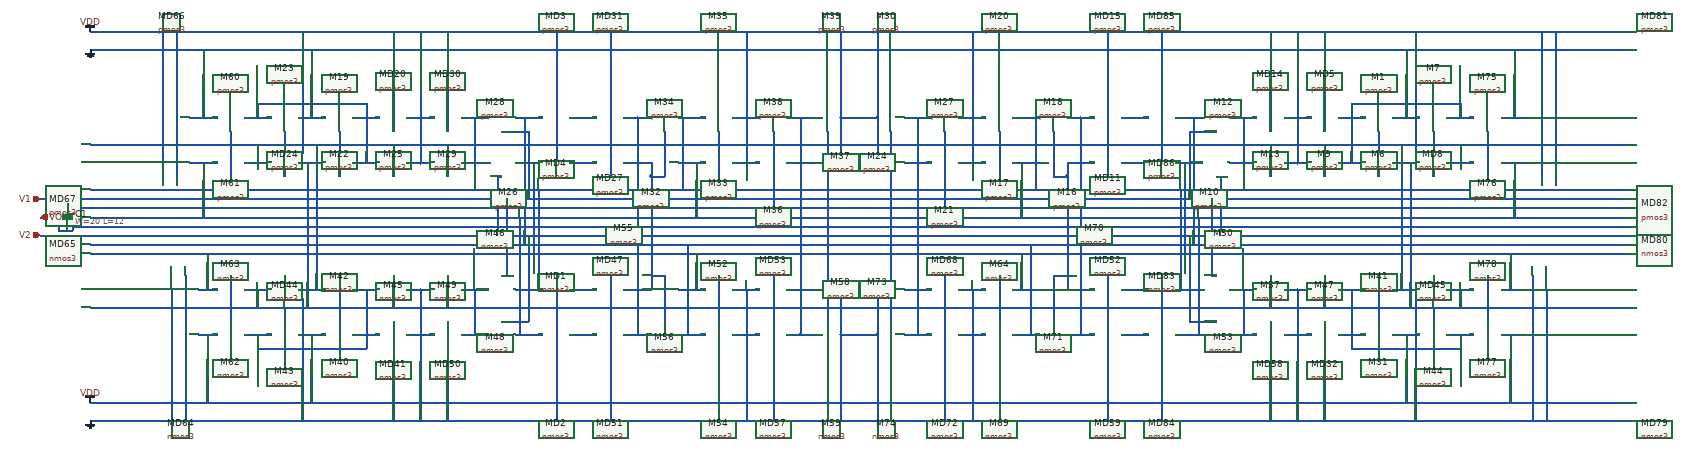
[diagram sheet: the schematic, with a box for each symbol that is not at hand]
v {xschem version=2.9.9 file_version=1.2 }
G {}
K {}
V {}
S {}
E {}
N -640 950 -630 950 { lab=#net1}
N 390 570 390 670 { lab=VDD}
N 270 570 330 570 { lab=VOUT}
N 240 600 240 700 { lab=#net2}
N 360 600 360 700 { lab=#net2}
N 300 950 330 950 { lab=VOUT}
N 300 1050 330 1050 { lab=VOUT}
N 390 950 390 1050 { lab=GND}
N 360 920 360 1020 { lab=#net2}
N 390 380 390 570 { lab=VDD}
N 180 380 180 670 { lab=VDD}
N 150 670 210 670 { lab=VDD}
N 150 570 180 570 { lab=VDD}
N 180 570 210 570 { lab=VDD}
N 30 570 90 570 { lab=#net3}
N 30 670 90 670 { lab=#net4}
N 0 600 0 700 { lab=#net5}
N 240 700 240 770 { lab=#net2}
N -60 570 -30 570 { lab=#net2}
N -60 570 -60 770 { lab=#net2}
N -30 670 -30 700 { lab=#net5}
N -30 700 0 700 { lab=#net5}
N -60 770 -60 1050 { lab=#net2}
N -60 1050 -30 1050 { lab=#net2}
N 150 950 210 950 { lab=GND}
N 180 950 180 1240 { lab=GND}
N -30 700 -30 950 { lab=#net5}
N -30 920 0 920 { lab=#net5}
N 30 1050 90 1050 { lab=#net6}
N 30 950 90 950 { lab=#net7}
N -90 1050 -60 1050 { lab=#net2}
N -90 950 -30 950 { lab=#net5}
N -90 670 -30 670 { lab=#net5}
N -90 570 -60 570 { lab=#net2}
N 0 920 0 1020 { lab=#net5}
N 270 950 300 950 { lab=VOUT}
N 270 1050 300 1050 { lab=VOUT}
N 150 1050 180 1050 { lab=GND}
N 180 1050 210 1050 { lab=GND}
N -360 1020 -300 1020 { lab=V2}
N -330 950 -270 950 { lab=#net3}
N -330 1050 -270 1050 { lab=#net4}
N -450 950 -390 950 { lab=#net8}
N -450 1050 -390 1050 { lab=#net8}
N -420 950 -420 1050 { lab=#net8}
N 300 810 300 1050 { lab=VOUT}
N 300 570 300 810 { lab=VOUT}
N 270 670 300 670 { lab=VOUT}
N 300 670 330 670 { lab=VOUT}
N 40 570 40 730 { lab=#net3}
N 70 670 70 790 { lab=#net4}
N 240 920 240 1240 { lab=GND}
N -120 920 -120 1240 { lab=GND}
N -300 830 -300 1020 { lab=V2}
N -570 1050 -540 1050 { lab=GND}
N -540 1050 -510 1050 { lab=GND}
N -480 920 -480 990 { lab=#net9}
N -570 950 -540 950 { lab=GND}
N -540 950 -510 950 { lab=GND}
N -540 950 -540 1240 { lab=GND}
N -600 920 -600 990 { lab=#net9}
N -690 950 -640 950 { lab=#net1}
N -660 950 -660 1050 { lab=#net1}
N -690 1050 -630 1050 { lab=#net1}
N -720 990 -720 1020 { lab=#net9}
N -720 920 -720 990 { lab=#net9}
N -810 1050 -750 1050 { lab=VDD}
N -1030 1050 -990 1050 { lab=VDD}
N -930 1050 -870 1050 { lab=#net1}
N -960 990 -960 1020 { lab=#net9}
N -840 990 -840 1020 { lab=#net9}
N -810 950 -750 950 { lab=#net10}
N -930 950 -870 950 { lab=#net9}
N -900 950 -900 990 { lab=#net9}
N -330 570 -270 570 { lab=#net6}
N -330 670 -270 670 { lab=#net7}
N 50 850 50 1050 { lab=#net6}
N -310 570 -310 850 { lab=#net6}
N 70 870 70 950 { lab=#net7}
N -290 670 -290 870 { lab=#net7}
N -300 600 -300 750 { lab=V1}
N -360 600 -300 600 { lab=V1}
N -350 750 -350 920 { lab=V1}
N -360 920 -350 920 { lab=V1}
N -370 700 -370 830 { lab=V2}
N -370 700 -360 700 { lab=V2}
N -450 570 -390 570 { lab=#net11}
N -450 670 -390 670 { lab=#net11}
N -420 570 -420 670 { lab=#net11}
N -480 380 -480 600 { lab=VDD}
N -480 630 -480 700 { lab=#net10}
N -540 670 -510 670 { lab=VDD}
N -570 670 -540 670 { lab=VDD}
N -570 570 -540 570 { lab=VDD}
N -540 570 -510 570 { lab=VDD}
N -540 380 -540 670 { lab=VDD}
N -600 380 -600 600 { lab=VDD}
N -690 670 -630 670 { lab=#net12}
N -660 570 -660 670 { lab=#net12}
N -690 570 -630 570 { lab=#net12}
N -600 630 -600 700 { lab=#net10}
N -810 570 -750 570 { lab=GND}
N -720 600 -720 630 { lab=#net10}
N -840 600 -840 630 { lab=#net10}
N -930 570 -870 570 { lab=#net12}
N -780 1050 -780 1200 { lab=VDD}
N -660 1050 -660 1080 { lab=#net1}
N -900 1080 -660 1080 { lab=#net1}
N -900 1050 -900 1080 { lab=#net1}
N -1010 1050 -1010 1200 { lab=VDD}
N -1030 950 -990 950 { lab=#net7}
N -780 420 -780 570 { lab=GND}
N -660 540 -660 570 { lab=#net12}
N -900 540 -660 540 { lab=#net12}
N -900 540 -900 570 { lab=#net12}
N -1050 570 -990 570 { lab=GND}
N -1020 420 -1020 570 { lab=GND}
N -960 600 -960 630 { lab=#net10}
N -720 630 -720 700 { lab=#net10}
N -810 670 -750 670 { lab=#net9}
N -930 670 -900 670 { lab=#net10}
N -900 670 -870 670 { lab=#net10}
N -1050 670 -990 670 { lab=#net4}
N -1080 380 -1080 700 { lab=VDD}
N -1060 920 -1060 1240 { lab=GND}
N -1010 870 -1010 950 { lab=#net7}
N -1090 950 -1090 1240 { lab=GND}
N -1110 380 -1110 670 { lab=VDD}
N -120 380 -120 700 { lab=VDD}
N 390 1050 390 1240 { lab=GND}
N -840 920 -840 970 { lab=GND}
N 120 600 120 630 { lab=#net10}
N 120 630 120 700 { lab=#net10}
N -600 1020 -600 1240 { lab=GND}
N -480 1020 -480 1240 { lab=GND}
N -770 630 -770 950 { lab=#net10}
N -960 630 -960 700 { lab=#net10}
N -900 630 -900 670 { lab=#net10}
N -840 650 -840 700 { lab=VDD}
N -840 650 -800 650 { lab=VDD}
N -800 380 -800 650 { lab=VDD}
N -840 970 -800 970 { lab=GND}
N -800 970 -800 1240 { lab=GND}
N -790 670 -790 990 { lab=#net9}
N -960 920 -960 990 { lab=#net9}
N -280 730 -280 950 { lab=#net3}
N -320 790 -320 1050 { lab=#net4}
N -1020 670 -1020 790 { lab=#net4}
N -1310 760 -1310 770 { lab=#net2}
N -1320 760 -1310 760 { lab=#net2}
N -1310 810 -1310 820 { lab=VOUT}
N -1320 820 -1310 820 { lab=VOUT}
N -1330 820 -1320 820 { lab=VOUT}
N -1270 1200 310 1200 { lab=VDD}
N -1270 1240 310 1240 { lab=GND}
N -1270 380 310 380 { lab=VDD}
N -1270 420 310 420 { lab=GND}
N -1310 770 -1270 770 { lab=#net2}
N -1310 810 -1270 810 { lab=VOUT}
N -1340 820 -1330 820 { lab=VOUT}
N -1340 790 -1340 820 { lab=VOUT}
N -1380 790 -1340 790 { lab=VOUT}
N -1380 830 -1270 830 { lab=V2}
N -1380 750 -1270 750 { lab=V1}
N 390 570 430 570 { lab=VDD}
N 390 670 430 670 { lab=VDD}
N 390 950 430 950 { lab=GND}
N 390 1050 430 1050 { lab=GND}
N 120 990 120 1020 { lab=#net9}
N 120 920 120 990 { lab=#net9}
N 360 700 360 770 { lab=#net2}
N 360 770 360 920 { lab=#net2}
N -1270 990 310 990 { lab=#net9}
N -1270 870 310 870 { lab=#net7}
N -1270 850 310 850 { lab=#net6}
N -1270 830 310 830 { lab=V2}
N -1270 810 310 810 { lab=VOUT}
N -1270 790 310 790 { lab=#net4}
N -1270 770 310 770 { lab=#net2}
N -1270 750 310 750 { lab=V1}
N -1270 730 310 730 { lab=#net3}
N -210 570 -150 570 { lab=#net13}
N -210 670 -150 670 { lab=#net14}
N -210 950 -150 950 { lab=#net15}
N -210 1050 -150 1050 { lab=#net16}
N -240 920 -240 1240 { lab=GND}
N -240 380 -240 700 { lab=VDD}
N 310 990 430 990 { lab=#net9}
N 310 1200 430 1200 { lab=VDD}
N 310 1240 430 1240 { lab=GND}
N 310 730 430 730 { lab=#net3}
N 310 750 430 750 { lab=V1}
N 310 770 430 770 { lab=#net2}
N 310 790 430 790 { lab=#net4}
N 310 810 430 810 { lab=VOUT}
N 310 830 430 830 { lab=V2}
N 310 850 430 850 { lab=#net6}
N 310 870 430 870 { lab=#net7}
N 310 420 430 420 { lab=GND}
N 310 380 430 380 { lab=VDD}
N -1270 630 430 630 { lab=#net10}
N 1490 950 1500 950 { lab=#net17}
N 470 570 470 670 { lab=VDD}
N 530 570 590 570 { lab=VOUT}
N 620 600 620 700 { lab=#net2}
N 500 600 500 700 { lab=#net2}
N 530 950 560 950 { lab=VOUT}
N 530 1050 560 1050 { lab=VOUT}
N 470 950 470 1050 { lab=GND}
N 500 920 500 1020 { lab=#net2}
N 470 380 470 570 { lab=VDD}
N 680 380 680 670 { lab=VDD}
N 650 670 710 670 { lab=VDD}
N 680 570 710 570 { lab=VDD}
N 650 570 680 570 { lab=VDD}
N 770 570 830 570 { lab=#net3}
N 770 670 830 670 { lab=#net4}
N 860 600 860 700 { lab=#net18}
N 620 700 620 770 { lab=#net2}
N 890 570 920 570 { lab=#net2}
N 920 570 920 770 { lab=#net2}
N 890 670 890 700 { lab=#net18}
N 860 700 890 700 { lab=#net18}
N 920 770 920 1050 { lab=#net2}
N 890 1050 920 1050 { lab=#net2}
N 650 950 710 950 { lab=GND}
N 680 950 680 1240 { lab=GND}
N 890 700 890 950 { lab=#net18}
N 860 920 890 920 { lab=#net18}
N 770 1050 830 1050 { lab=#net6}
N 770 950 830 950 { lab=#net7}
N 920 1050 950 1050 { lab=#net2}
N 890 950 950 950 { lab=#net18}
N 890 670 950 670 { lab=#net18}
N 920 570 950 570 { lab=#net2}
N 860 920 860 1020 { lab=#net18}
N 560 950 590 950 { lab=VOUT}
N 560 1050 590 1050 { lab=VOUT}
N 680 1050 710 1050 { lab=GND}
N 650 1050 680 1050 { lab=GND}
N 1160 1020 1220 1020 { lab=V2}
N 1130 950 1190 950 { lab=#net3}
N 1130 1050 1190 1050 { lab=#net4}
N 1250 950 1310 950 { lab=#net19}
N 1250 1050 1310 1050 { lab=#net19}
N 1280 950 1280 1050 { lab=#net19}
N 560 810 560 1050 { lab=VOUT}
N 560 570 560 810 { lab=VOUT}
N 560 670 590 670 { lab=VOUT}
N 530 670 560 670 { lab=VOUT}
N 820 570 820 730 { lab=#net3}
N 790 670 790 790 { lab=#net4}
N 620 920 620 1240 { lab=GND}
N 980 920 980 1240 { lab=GND}
N 1160 830 1160 1020 { lab=V2}
N 1400 1050 1430 1050 { lab=GND}
N 1370 1050 1400 1050 { lab=GND}
N 1340 920 1340 990 { lab=#net9}
N 1400 950 1430 950 { lab=GND}
N 1370 950 1400 950 { lab=GND}
N 1400 950 1400 1240 { lab=GND}
N 1460 920 1460 990 { lab=#net9}
N 1500 950 1550 950 { lab=#net17}
N 1520 950 1520 1050 { lab=#net17}
N 1490 1050 1550 1050 { lab=#net17}
N 1580 990 1580 1020 { lab=#net9}
N 1580 920 1580 990 { lab=#net9}
N 1610 1050 1670 1050 { lab=VDD}
N 1850 1050 1890 1050 { lab=VDD}
N 1730 1050 1790 1050 { lab=#net17}
N 1820 990 1820 1020 { lab=#net9}
N 1700 990 1700 1020 { lab=#net9}
N 1610 950 1670 950 { lab=#net10}
N 1730 950 1790 950 { lab=#net9}
N 1760 950 1760 990 { lab=#net9}
N 1130 570 1190 570 { lab=#net6}
N 1130 670 1190 670 { lab=#net7}
N 810 850 810 1050 { lab=#net6}
N 1170 570 1170 850 { lab=#net6}
N 790 870 790 950 { lab=#net7}
N 1150 670 1150 870 { lab=#net7}
N 1160 600 1160 750 { lab=V1}
N 1160 600 1220 600 { lab=V1}
N 1210 750 1210 920 { lab=V1}
N 1210 920 1220 920 { lab=V1}
N 1230 700 1230 830 { lab=V2}
N 1220 700 1230 700 { lab=V2}
N 1250 570 1310 570 { lab=#net20}
N 1250 670 1310 670 { lab=#net20}
N 1280 570 1280 670 { lab=#net20}
N 1340 380 1340 600 { lab=VDD}
N 1340 630 1340 700 { lab=#net10}
N 1370 670 1400 670 { lab=VDD}
N 1400 670 1430 670 { lab=VDD}
N 1400 570 1430 570 { lab=VDD}
N 1370 570 1400 570 { lab=VDD}
N 1400 380 1400 670 { lab=VDD}
N 1460 380 1460 600 { lab=VDD}
N 1490 670 1550 670 { lab=#net21}
N 1520 570 1520 670 { lab=#net21}
N 1490 570 1550 570 { lab=#net21}
N 1460 630 1460 700 { lab=#net10}
N 1610 570 1670 570 { lab=GND}
N 1580 600 1580 630 { lab=#net10}
N 1700 600 1700 630 { lab=#net10}
N 1730 570 1790 570 { lab=#net21}
N 1640 1050 1640 1200 { lab=VDD}
N 1520 1050 1520 1080 { lab=#net17}
N 1520 1080 1760 1080 { lab=#net17}
N 1760 1050 1760 1080 { lab=#net17}
N 1870 1050 1870 1200 { lab=VDD}
N 1850 950 1890 950 { lab=#net7}
N 1640 420 1640 570 { lab=GND}
N 1520 540 1520 570 { lab=#net21}
N 1520 540 1760 540 { lab=#net21}
N 1760 540 1760 570 { lab=#net21}
N 1850 570 1910 570 { lab=GND}
N 1880 420 1880 570 { lab=GND}
N 1820 600 1820 630 { lab=#net10}
N 1580 630 1580 700 { lab=#net10}
N 1610 670 1670 670 { lab=#net9}
N 1760 670 1790 670 { lab=#net10}
N 1730 670 1760 670 { lab=#net10}
N 1850 670 1910 670 { lab=#net4}
N 1940 380 1940 700 { lab=VDD}
N 1920 920 1920 1240 { lab=GND}
N 1870 870 1870 950 { lab=#net7}
N 1950 950 1950 1240 { lab=GND}
N 1970 380 1970 670 { lab=VDD}
N 980 380 980 700 { lab=VDD}
N 470 1050 470 1240 { lab=GND}
N 1700 920 1700 970 { lab=GND}
N 740 600 740 630 { lab=#net10}
N 740 630 740 700 { lab=#net10}
N 1460 1020 1460 1240 { lab=GND}
N 1340 1020 1340 1240 { lab=GND}
N 1630 630 1630 950 { lab=#net10}
N 1820 630 1820 700 { lab=#net10}
N 1760 630 1760 670 { lab=#net10}
N 1700 650 1700 700 { lab=VDD}
N 1660 650 1700 650 { lab=VDD}
N 1660 380 1660 650 { lab=VDD}
N 1660 970 1700 970 { lab=GND}
N 1660 970 1660 1240 { lab=GND}
N 1650 670 1650 990 { lab=#net9}
N 1820 920 1820 990 { lab=#net9}
N 1140 730 1140 950 { lab=#net3}
N 1180 790 1180 1050 { lab=#net4}
N 1880 670 1880 790 { lab=#net4}
N 550 1200 2130 1200 { lab=VDD}
N 550 1240 2130 1240 { lab=GND}
N 550 380 2130 380 { lab=VDD}
N 550 420 2130 420 { lab=GND}
N 430 570 470 570 { lab=VDD}
N 430 670 470 670 { lab=VDD}
N 430 950 470 950 { lab=GND}
N 430 1050 470 1050 { lab=GND}
N 740 990 740 1020 { lab=#net9}
N 740 920 740 990 { lab=#net9}
N 500 700 500 770 { lab=#net2}
N 500 770 500 920 { lab=#net2}
N 550 990 2130 990 { lab=#net9}
N 550 870 2130 870 { lab=#net7}
N 550 850 2130 850 { lab=#net6}
N 550 830 2130 830 { lab=V2}
N 550 810 2130 810 { lab=VOUT}
N 550 790 2130 790 { lab=#net4}
N 550 770 2130 770 { lab=#net2}
N 550 750 2130 750 { lab=V1}
N 550 730 2130 730 { lab=#net3}
N 1010 570 1070 570 { lab=#net22}
N 1010 670 1070 670 { lab=#net23}
N 1010 950 1070 950 { lab=#net24}
N 1010 1050 1070 1050 { lab=#net25}
N 1100 920 1100 1240 { lab=GND}
N 1100 380 1100 700 { lab=VDD}
N 430 990 550 990 { lab=#net9}
N 430 1200 550 1200 { lab=VDD}
N 430 1240 550 1240 { lab=GND}
N 430 730 550 730 { lab=#net3}
N 430 750 550 750 { lab=V1}
N 430 770 550 770 { lab=#net2}
N 430 790 550 790 { lab=#net4}
N 430 810 550 810 { lab=VOUT}
N 430 830 550 830 { lab=V2}
N 430 850 550 850 { lab=#net6}
N 430 870 550 870 { lab=#net7}
N 430 420 550 420 { lab=GND}
N 430 380 550 380 { lab=VDD}
N 430 630 2130 630 { lab=#net10}
C {madvlsi/pmos3.sym} -720 570 3 0 {name=M19
L=.6
W=1.5
body=VDD
nf=1
mult=1
ad="'int((nf+1)/2) * W/nf * 0.29'" 
pd="'2*int((nf+1)/2) * (W/nf + 0.29)'"
as="'int((nf+2)/2) * W/nf * 0.29'" 
ps="'2*int((nf+2)/2) * (W/nf + 0.29)'"
nrd="'0.29 / W'" nrs="'0.29 / W'"
sa=0 sb=0 sd=0
model=pfet_01v8
spiceprefix=X
}
C {madvlsi/pmos3.sym} -600 570 3 0 {name=MD20
L=.6
W=1.5
body=VDD
nf=1
mult=1
ad="'int((nf+1)/2) * W/nf * 0.29'" 
pd="'2*int((nf+1)/2) * (W/nf + 0.29)'"
as="'int((nf+2)/2) * W/nf * 0.29'" 
ps="'2*int((nf+2)/2) * (W/nf + 0.29)'"
nrd="'0.29 / W'" nrs="'0.29 / W'"
sa=0 sb=0 sd=0
model=pfet_01v8
spiceprefix=X
}
C {madvlsi/pmos3.sym} -720 670 3 0 {name=M22
L=.6
W=1.5
body=VDD
nf=1
mult=1
ad="'int((nf+1)/2) * W/nf * 0.29'" 
pd="'2*int((nf+1)/2) * (W/nf + 0.29)'"
as="'int((nf+2)/2) * W/nf * 0.29'" 
ps="'2*int((nf+2)/2) * (W/nf + 0.29)'"
nrd="'0.29 / W'" nrs="'0.29 / W'"
sa=0 sb=0 sd=0
model=pfet_01v8
spiceprefix=X
}
C {madvlsi/pmos3.sym} -840 570 3 0 {name=M23
L=.6
W=1.5
body=VDD
nf=1
mult=1
ad="'int((nf+1)/2) * W/nf * 0.29'" 
pd="'2*int((nf+1)/2) * (W/nf + 0.29)'"
as="'int((nf+2)/2) * W/nf * 0.29'" 
ps="'2*int((nf+2)/2) * (W/nf + 0.29)'"
nrd="'0.29 / W'" nrs="'0.29 / W'"
sa=0 sb=0 sd=0
model=pfet_01v8
spiceprefix=X
}
C {madvlsi/pmos3.sym} -840 670 3 0 {name=MD24
L=.6
W=1.5
body=VDD
nf=1
mult=1
ad="'int((nf+1)/2) * W/nf * 0.29'" 
pd="'2*int((nf+1)/2) * (W/nf + 0.29)'"
as="'int((nf+2)/2) * W/nf * 0.29'" 
ps="'2*int((nf+2)/2) * (W/nf + 0.29)'"
nrd="'0.29 / W'" nrs="'0.29 / W'"
sa=0 sb=0 sd=0
model=pfet_01v8
spiceprefix=X
}
C {madvlsi/pmos3.sym} -600 670 3 0 {name=M25
L=.6
W=1.5
body=VDD
nf=1
mult=1
ad="'int((nf+1)/2) * W/nf * 0.29'" 
pd="'2*int((nf+1)/2) * (W/nf + 0.29)'"
as="'int((nf+2)/2) * W/nf * 0.29'" 
ps="'2*int((nf+2)/2) * (W/nf + 0.29)'"
nrd="'0.29 / W'" nrs="'0.29 / W'"
sa=0 sb=0 sd=0
model=pfet_01v8
spiceprefix=X
}
C {madvlsi/pmos3.sym} -360 670 3 0 {name=M26
L=.6
W=1.5
body=VDD
nf=1
mult=1
ad="'int((nf+1)/2) * W/nf * 0.29'" 
pd="'2*int((nf+1)/2) * (W/nf + 0.29)'"
as="'int((nf+2)/2) * W/nf * 0.29'" 
ps="'2*int((nf+2)/2) * (W/nf + 0.29)'"
nrd="'0.29 / W'" nrs="'0.29 / W'"
sa=0 sb=0 sd=0
model=pfet_01v8
spiceprefix=X
}
C {madvlsi/pmos3.sym} -120 670 3 0 {name=MD27
L=.6
W=1.5
body=VDD
nf=1
mult=1
ad="'int((nf+1)/2) * W/nf * 0.29'" 
pd="'2*int((nf+1)/2) * (W/nf + 0.29)'"
as="'int((nf+2)/2) * W/nf * 0.29'" 
ps="'2*int((nf+2)/2) * (W/nf + 0.29)'"
nrd="'0.29 / W'" nrs="'0.29 / W'"
sa=0 sb=0 sd=0
model=pfet_01v8
spiceprefix=X
}
C {madvlsi/pmos3.sym} -360 570 3 0 {name=M28
L=.6
W=1.5
body=VDD
nf=1
mult=1
ad="'int((nf+1)/2) * W/nf * 0.29'" 
pd="'2*int((nf+1)/2) * (W/nf + 0.29)'"
as="'int((nf+2)/2) * W/nf * 0.29'" 
ps="'2*int((nf+2)/2) * (W/nf + 0.29)'"
nrd="'0.29 / W'" nrs="'0.29 / W'"
sa=0 sb=0 sd=0
model=pfet_01v8
spiceprefix=X
}
C {madvlsi/pmos3.sym} -480 670 3 0 {name=M29
L=.6
W=1.5
body=VDD
nf=1
mult=1
ad="'int((nf+1)/2) * W/nf * 0.29'" 
pd="'2*int((nf+1)/2) * (W/nf + 0.29)'"
as="'int((nf+2)/2) * W/nf * 0.29'" 
ps="'2*int((nf+2)/2) * (W/nf + 0.29)'"
nrd="'0.29 / W'" nrs="'0.29 / W'"
sa=0 sb=0 sd=0
model=pfet_01v8
spiceprefix=X
}
C {madvlsi/pmos3.sym} -480 570 3 0 {name=MD30
L=.6
W=1.5
body=VDD
nf=1
mult=1
ad="'int((nf+1)/2) * W/nf * 0.29'" 
pd="'2*int((nf+1)/2) * (W/nf + 0.29)'"
as="'int((nf+2)/2) * W/nf * 0.29'" 
ps="'2*int((nf+2)/2) * (W/nf + 0.29)'"
nrd="'0.29 / W'" nrs="'0.29 / W'"
sa=0 sb=0 sd=0
model=pfet_01v8
spiceprefix=X
}
C {madvlsi/pmos3.sym} -120 570 3 0 {name=MD31
L=.6
W=1.5
body=VDD
nf=1
mult=1
ad="'int((nf+1)/2) * W/nf * 0.29'" 
pd="'2*int((nf+1)/2) * (W/nf + 0.29)'"
as="'int((nf+2)/2) * W/nf * 0.29'" 
ps="'2*int((nf+2)/2) * (W/nf + 0.29)'"
nrd="'0.29 / W'" nrs="'0.29 / W'"
sa=0 sb=0 sd=0
model=pfet_01v8
spiceprefix=X
}
C {madvlsi/pmos3.sym} 0 670 3 0 {name=M32
L=.6
W=1.5
body=VDD
nf=1
mult=1
ad="'int((nf+1)/2) * W/nf * 0.29'" 
pd="'2*int((nf+1)/2) * (W/nf + 0.29)'"
as="'int((nf+2)/2) * W/nf * 0.29'" 
ps="'2*int((nf+2)/2) * (W/nf + 0.29)'"
nrd="'0.29 / W'" nrs="'0.29 / W'"
sa=0 sb=0 sd=0
model=pfet_01v8
spiceprefix=X
}
C {madvlsi/pmos3.sym} 120 670 3 0 {name=M33
L=.6
W=1.5
body=VDD
nf=1
mult=1
ad="'int((nf+1)/2) * W/nf * 0.29'" 
pd="'2*int((nf+1)/2) * (W/nf + 0.29)'"
as="'int((nf+2)/2) * W/nf * 0.29'" 
ps="'2*int((nf+2)/2) * (W/nf + 0.29)'"
nrd="'0.29 / W'" nrs="'0.29 / W'"
sa=0 sb=0 sd=0
model=pfet_01v8
spiceprefix=X
}
C {madvlsi/pmos3.sym} 0 570 3 0 {name=M34
L=.6
W=1.5
body=VDD
nf=1
mult=1
ad="'int((nf+1)/2) * W/nf * 0.29'" 
pd="'2*int((nf+1)/2) * (W/nf + 0.29)'"
as="'int((nf+2)/2) * W/nf * 0.29'" 
ps="'2*int((nf+2)/2) * (W/nf + 0.29)'"
nrd="'0.29 / W'" nrs="'0.29 / W'"
sa=0 sb=0 sd=0
model=pfet_01v8
spiceprefix=X
}
C {madvlsi/pmos3.sym} 120 570 3 0 {name=M35
L=.6
W=1.5
body=VDD
nf=1
mult=1
ad="'int((nf+1)/2) * W/nf * 0.29'" 
pd="'2*int((nf+1)/2) * (W/nf + 0.29)'"
as="'int((nf+2)/2) * W/nf * 0.29'" 
ps="'2*int((nf+2)/2) * (W/nf + 0.29)'"
nrd="'0.29 / W'" nrs="'0.29 / W'"
sa=0 sb=0 sd=0
model=pfet_01v8
spiceprefix=X
}
C {madvlsi/pmos3.sym} 240 670 3 0 {name=M36
L=.6
W=1.5
body=VDD
nf=1
mult=1
ad="'int((nf+1)/2) * W/nf * 0.29'" 
pd="'2*int((nf+1)/2) * (W/nf + 0.29)'"
as="'int((nf+2)/2) * W/nf * 0.29'" 
ps="'2*int((nf+2)/2) * (W/nf + 0.29)'"
nrd="'0.29 / W'" nrs="'0.29 / W'"
sa=0 sb=0 sd=0
model=pfet_01v8
spiceprefix=X
}
C {madvlsi/pmos3.sym} 360 670 3 0 {name=M37
L=.6
W=1.5
body=VDD
nf=1
mult=1
ad="'int((nf+1)/2) * W/nf * 0.29'" 
pd="'2*int((nf+1)/2) * (W/nf + 0.29)'"
as="'int((nf+2)/2) * W/nf * 0.29'" 
ps="'2*int((nf+2)/2) * (W/nf + 0.29)'"
nrd="'0.29 / W'" nrs="'0.29 / W'"
sa=0 sb=0 sd=0
model=pfet_01v8
spiceprefix=X
}
C {madvlsi/pmos3.sym} 240 570 3 0 {name=M38
L=.6
W=1.5
body=VDD
nf=1
mult=1
ad="'int((nf+1)/2) * W/nf * 0.29'" 
pd="'2*int((nf+1)/2) * (W/nf + 0.29)'"
as="'int((nf+2)/2) * W/nf * 0.29'" 
ps="'2*int((nf+2)/2) * (W/nf + 0.29)'"
nrd="'0.29 / W'" nrs="'0.29 / W'"
sa=0 sb=0 sd=0
model=pfet_01v8
spiceprefix=X
}
C {madvlsi/pmos3.sym} 360 570 3 0 {name=M39
L=.6
W=1.5
body=VDD
nf=1
mult=1
ad="'int((nf+1)/2) * W/nf * 0.29'" 
pd="'2*int((nf+1)/2) * (W/nf + 0.29)'"
as="'int((nf+2)/2) * W/nf * 0.29'" 
ps="'2*int((nf+2)/2) * (W/nf + 0.29)'"
nrd="'0.29 / W'" nrs="'0.29 / W'"
sa=0 sb=0 sd=0
model=pfet_01v8
spiceprefix=X
}
C {madvlsi/nmos3.sym} -720 1050 1 0 {name=M40
L=.6
W=1.5
body=GND
nf=1
mult=1
ad="'int((nf+1)/2) * W/nf * 0.29'" 
pd="'2*int((nf+1)/2) * (W/nf + 0.29)'"
as="'int((nf+2)/2) * W/nf * 0.29'" 
ps="'2*int((nf+2)/2) * (W/nf + 0.29)'"
nrd="'0.29 / W'" nrs="'0.29 / W'"
sa=0 sb=0 sd=0
model=nfet_01v8
spiceprefix=X
}
C {madvlsi/nmos3.sym} -600 1050 1 0 {name=MD41
L=.6
W=1.5
body=GND
nf=1
mult=1
ad="'int((nf+1)/2) * W/nf * 0.29'" 
pd="'2*int((nf+1)/2) * (W/nf + 0.29)'"
as="'int((nf+2)/2) * W/nf * 0.29'" 
ps="'2*int((nf+2)/2) * (W/nf + 0.29)'"
nrd="'0.29 / W'" nrs="'0.29 / W'"
sa=0 sb=0 sd=0
model=nfet_01v8
spiceprefix=X
}
C {madvlsi/nmos3.sym} -720 950 1 0 {name=M42
L=.6
W=1.5
body=GND
nf=1
mult=1
ad="'int((nf+1)/2) * W/nf * 0.29'" 
pd="'2*int((nf+1)/2) * (W/nf + 0.29)'"
as="'int((nf+2)/2) * W/nf * 0.29'" 
ps="'2*int((nf+2)/2) * (W/nf + 0.29)'"
nrd="'0.29 / W'" nrs="'0.29 / W'"
sa=0 sb=0 sd=0
model=nfet_01v8
spiceprefix=X
}
C {madvlsi/nmos3.sym} -840 1050 1 0 {name=M43
L=.6
W=1.5
body=GND
nf=1
mult=1
ad="'int((nf+1)/2) * W/nf * 0.29'" 
pd="'2*int((nf+1)/2) * (W/nf + 0.29)'"
as="'int((nf+2)/2) * W/nf * 0.29'" 
ps="'2*int((nf+2)/2) * (W/nf + 0.29)'"
nrd="'0.29 / W'" nrs="'0.29 / W'"
sa=0 sb=0 sd=0
model=nfet_01v8
spiceprefix=X
}
C {madvlsi/nmos3.sym} -840 950 1 0 {name=MD44
L=.6
W=1.5
body=GND
nf=1
mult=1
ad="'int((nf+1)/2) * W/nf * 0.29'" 
pd="'2*int((nf+1)/2) * (W/nf + 0.29)'"
as="'int((nf+2)/2) * W/nf * 0.29'" 
ps="'2*int((nf+2)/2) * (W/nf + 0.29)'"
nrd="'0.29 / W'" nrs="'0.29 / W'"
sa=0 sb=0 sd=0
model=nfet_01v8
spiceprefix=X
}
C {madvlsi/nmos3.sym} -600 950 1 0 {name=M45
L=.6
W=1.5
body=GND
nf=1
mult=1
ad="'int((nf+1)/2) * W/nf * 0.29'" 
pd="'2*int((nf+1)/2) * (W/nf + 0.29)'"
as="'int((nf+2)/2) * W/nf * 0.29'" 
ps="'2*int((nf+2)/2) * (W/nf + 0.29)'"
nrd="'0.29 / W'" nrs="'0.29 / W'"
sa=0 sb=0 sd=0
model=nfet_01v8
spiceprefix=X
}
C {madvlsi/nmos3.sym} -360 950 1 0 {name=M46
L=.6
W=1.5
body=GND
nf=1
mult=1
ad="'int((nf+1)/2) * W/nf * 0.29'" 
pd="'2*int((nf+1)/2) * (W/nf + 0.29)'"
as="'int((nf+2)/2) * W/nf * 0.29'" 
ps="'2*int((nf+2)/2) * (W/nf + 0.29)'"
nrd="'0.29 / W'" nrs="'0.29 / W'"
sa=0 sb=0 sd=0
model=nfet_01v8
spiceprefix=X
}
C {madvlsi/nmos3.sym} -120 950 1 0 {name=MD47
L=.6
W=1.5
body=GND
nf=1
mult=1
ad="'int((nf+1)/2) * W/nf * 0.29'" 
pd="'2*int((nf+1)/2) * (W/nf + 0.29)'"
as="'int((nf+2)/2) * W/nf * 0.29'" 
ps="'2*int((nf+2)/2) * (W/nf + 0.29)'"
nrd="'0.29 / W'" nrs="'0.29 / W'"
sa=0 sb=0 sd=0
model=nfet_01v8
spiceprefix=X
}
C {madvlsi/nmos3.sym} -360 1050 1 0 {name=M48
L=.6
W=1.5
body=GND
nf=1
mult=1
ad="'int((nf+1)/2) * W/nf * 0.29'" 
pd="'2*int((nf+1)/2) * (W/nf + 0.29)'"
as="'int((nf+2)/2) * W/nf * 0.29'" 
ps="'2*int((nf+2)/2) * (W/nf + 0.29)'"
nrd="'0.29 / W'" nrs="'0.29 / W'"
sa=0 sb=0 sd=0
model=nfet_01v8
spiceprefix=X
}
C {madvlsi/nmos3.sym} -480 950 1 0 {name=M49
L=.6
W=1.5
body=GND
nf=1
mult=1
ad="'int((nf+1)/2) * W/nf * 0.29'" 
pd="'2*int((nf+1)/2) * (W/nf + 0.29)'"
as="'int((nf+2)/2) * W/nf * 0.29'" 
ps="'2*int((nf+2)/2) * (W/nf + 0.29)'"
nrd="'0.29 / W'" nrs="'0.29 / W'"
sa=0 sb=0 sd=0
model=nfet_01v8
spiceprefix=X
}
C {madvlsi/nmos3.sym} -480 1050 1 0 {name=MD50
L=.6
W=1.5
body=GND
nf=1
mult=1
ad="'int((nf+1)/2) * W/nf * 0.29'" 
pd="'2*int((nf+1)/2) * (W/nf + 0.29)'"
as="'int((nf+2)/2) * W/nf * 0.29'" 
ps="'2*int((nf+2)/2) * (W/nf + 0.29)'"
nrd="'0.29 / W'" nrs="'0.29 / W'"
sa=0 sb=0 sd=0
model=nfet_01v8
spiceprefix=X
}
C {madvlsi/nmos3.sym} -120 1050 1 0 {name=MD51
L=.6
W=1.5
body=GND
nf=1
mult=1
ad="'int((nf+1)/2) * W/nf * 0.29'" 
pd="'2*int((nf+1)/2) * (W/nf + 0.29)'"
as="'int((nf+2)/2) * W/nf * 0.29'" 
ps="'2*int((nf+2)/2) * (W/nf + 0.29)'"
nrd="'0.29 / W'" nrs="'0.29 / W'"
sa=0 sb=0 sd=0
model=nfet_01v8
spiceprefix=X
}
C {madvlsi/nmos3.sym} 120 950 1 0 {name=M52
L=.6
W=1.5
body=GND
nf=1
mult=1
ad="'int((nf+1)/2) * W/nf * 0.29'" 
pd="'2*int((nf+1)/2) * (W/nf + 0.29)'"
as="'int((nf+2)/2) * W/nf * 0.29'" 
ps="'2*int((nf+2)/2) * (W/nf + 0.29)'"
nrd="'0.29 / W'" nrs="'0.29 / W'"
sa=0 sb=0 sd=0
model=nfet_01v8
spiceprefix=X
}
C {madvlsi/nmos3.sym} 240 950 1 0 {name=MD53
L=.6
W=1.5
body=GND
nf=1
mult=1
ad="'int((nf+1)/2) * W/nf * 0.29'" 
pd="'2*int((nf+1)/2) * (W/nf + 0.29)'"
as="'int((nf+2)/2) * W/nf * 0.29'" 
ps="'2*int((nf+2)/2) * (W/nf + 0.29)'"
nrd="'0.29 / W'" nrs="'0.29 / W'"
sa=0 sb=0 sd=0
model=nfet_01v8
spiceprefix=X
}
C {madvlsi/nmos3.sym} 120 1050 1 0 {name=M54
L=.6
W=1.5
body=GND
nf=1
mult=1
ad="'int((nf+1)/2) * W/nf * 0.29'" 
pd="'2*int((nf+1)/2) * (W/nf + 0.29)'"
as="'int((nf+2)/2) * W/nf * 0.29'" 
ps="'2*int((nf+2)/2) * (W/nf + 0.29)'"
nrd="'0.29 / W'" nrs="'0.29 / W'"
sa=0 sb=0 sd=0
model=nfet_01v8
spiceprefix=X
}
C {madvlsi/nmos3.sym} 0 950 1 0 {name=M55
L=.6
W=1.5
body=GND
nf=1
mult=1
ad="'int((nf+1)/2) * W/nf * 0.29'" 
pd="'2*int((nf+1)/2) * (W/nf + 0.29)'"
as="'int((nf+2)/2) * W/nf * 0.29'" 
ps="'2*int((nf+2)/2) * (W/nf + 0.29)'"
nrd="'0.29 / W'" nrs="'0.29 / W'"
sa=0 sb=0 sd=0
model=nfet_01v8
spiceprefix=X
}
C {madvlsi/nmos3.sym} 0 1050 1 0 {name=M56
L=.6
W=1.5
body=GND
nf=1
mult=1
ad="'int((nf+1)/2) * W/nf * 0.29'" 
pd="'2*int((nf+1)/2) * (W/nf + 0.29)'"
as="'int((nf+2)/2) * W/nf * 0.29'" 
ps="'2*int((nf+2)/2) * (W/nf + 0.29)'"
nrd="'0.29 / W'" nrs="'0.29 / W'"
sa=0 sb=0 sd=0
model=nfet_01v8
spiceprefix=X
}
C {madvlsi/nmos3.sym} 240 1050 1 0 {name=MD57
L=.6
W=1.5
body=GND
nf=1
mult=1
ad="'int((nf+1)/2) * W/nf * 0.29'" 
pd="'2*int((nf+1)/2) * (W/nf + 0.29)'"
as="'int((nf+2)/2) * W/nf * 0.29'" 
ps="'2*int((nf+2)/2) * (W/nf + 0.29)'"
nrd="'0.29 / W'" nrs="'0.29 / W'"
sa=0 sb=0 sd=0
model=nfet_01v8
spiceprefix=X
}
C {madvlsi/nmos3.sym} 360 950 1 0 {name=M58
L=.6
W=1.5
body=GND
nf=1
mult=1
ad="'int((nf+1)/2) * W/nf * 0.29'" 
pd="'2*int((nf+1)/2) * (W/nf + 0.29)'"
as="'int((nf+2)/2) * W/nf * 0.29'" 
ps="'2*int((nf+2)/2) * (W/nf + 0.29)'"
nrd="'0.29 / W'" nrs="'0.29 / W'"
sa=0 sb=0 sd=0
model=nfet_01v8
spiceprefix=X
}
C {madvlsi/nmos3.sym} 360 1050 1 0 {name=M59
L=.6
W=1.5
body=GND
nf=1
mult=1
ad="'int((nf+1)/2) * W/nf * 0.29'" 
pd="'2*int((nf+1)/2) * (W/nf + 0.29)'"
as="'int((nf+2)/2) * W/nf * 0.29'" 
ps="'2*int((nf+2)/2) * (W/nf + 0.29)'"
nrd="'0.29 / W'" nrs="'0.29 / W'"
sa=0 sb=0 sd=0
model=nfet_01v8
spiceprefix=X
}
C {madvlsi/pmos3.sym} -960 570 3 0 {name=M60
L=.6
W=1.5
body=VDD
nf=1
mult=1
ad="'int((nf+1)/2) * W/nf * 0.29'" 
pd="'2*int((nf+1)/2) * (W/nf + 0.29)'"
as="'int((nf+2)/2) * W/nf * 0.29'" 
ps="'2*int((nf+2)/2) * (W/nf + 0.29)'"
nrd="'0.29 / W'" nrs="'0.29 / W'"
sa=0 sb=0 sd=0
model=pfet_01v8
spiceprefix=X
}
C {madvlsi/pmos3.sym} -960 670 3 0 {name=M61
L=.6
W=1.5
body=VDD
nf=1
mult=1
ad="'int((nf+1)/2) * W/nf * 0.29'" 
pd="'2*int((nf+1)/2) * (W/nf + 0.29)'"
as="'int((nf+2)/2) * W/nf * 0.29'" 
ps="'2*int((nf+2)/2) * (W/nf + 0.29)'"
nrd="'0.29 / W'" nrs="'0.29 / W'"
sa=0 sb=0 sd=0
model=pfet_01v8
spiceprefix=X
}
C {madvlsi/nmos3.sym} -960 1050 1 0 {name=M62
L=.6
W=1.5
body=GND
nf=1
mult=1
ad="'int((nf+1)/2) * W/nf * 0.29'" 
pd="'2*int((nf+1)/2) * (W/nf + 0.29)'"
as="'int((nf+2)/2) * W/nf * 0.29'" 
ps="'2*int((nf+2)/2) * (W/nf + 0.29)'"
nrd="'0.29 / W'" nrs="'0.29 / W'"
sa=0 sb=0 sd=0
model=nfet_01v8
spiceprefix=X
}
C {madvlsi/nmos3.sym} -960 950 1 0 {name=M63
L=.6
W=1.5
body=GND
nf=1
mult=1
ad="'int((nf+1)/2) * W/nf * 0.29'" 
pd="'2*int((nf+1)/2) * (W/nf + 0.29)'"
as="'int((nf+2)/2) * W/nf * 0.29'" 
ps="'2*int((nf+2)/2) * (W/nf + 0.29)'"
nrd="'0.29 / W'" nrs="'0.29 / W'"
sa=0 sb=0 sd=0
model=nfet_01v8
spiceprefix=X
}
C {madvlsi/nmos3.sym} -1060 1050 1 0 {name=MD64
L=.6
W=1.5
body=GND
nf=1
mult=1
ad="'int((nf+1)/2) * W/nf * 0.29'" 
pd="'2*int((nf+1)/2) * (W/nf + 0.29)'"
as="'int((nf+2)/2) * W/nf * 0.29'" 
ps="'2*int((nf+2)/2) * (W/nf + 0.29)'"
nrd="'0.29 / W'" nrs="'0.29 / W'"
sa=0 sb=0 sd=0
model=nfet_01v8
spiceprefix=X
}
C {madvlsi/nmos3.sym} -1060 950 1 0 {name=MD65
L=.6
W=1.5
body=GND
nf=1
mult=1
ad="'int((nf+1)/2) * W/nf * 0.29'" 
pd="'2*int((nf+1)/2) * (W/nf + 0.29)'"
as="'int((nf+2)/2) * W/nf * 0.29'" 
ps="'2*int((nf+2)/2) * (W/nf + 0.29)'"
nrd="'0.29 / W'" nrs="'0.29 / W'"
sa=0 sb=0 sd=0
model=nfet_01v8
spiceprefix=X
}
C {madvlsi/pmos3.sym} -1080 570 3 0 {name=MD66
L=.6
W=1.5
body=VDD
nf=1
mult=1
ad="'int((nf+1)/2) * W/nf * 0.29'" 
pd="'2*int((nf+1)/2) * (W/nf + 0.29)'"
as="'int((nf+2)/2) * W/nf * 0.29'" 
ps="'2*int((nf+2)/2) * (W/nf + 0.29)'"
nrd="'0.29 / W'" nrs="'0.29 / W'"
sa=0 sb=0 sd=0
model=pfet_01v8
spiceprefix=X
}
C {madvlsi/pmos3.sym} -1080 670 3 0 {name=MD67
L=.6
W=1.5
body=VDD
nf=1
mult=1
ad="'int((nf+1)/2) * W/nf * 0.29'" 
pd="'2*int((nf+1)/2) * (W/nf + 0.29)'"
as="'int((nf+2)/2) * W/nf * 0.29'" 
ps="'2*int((nf+2)/2) * (W/nf + 0.29)'"
nrd="'0.29 / W'" nrs="'0.29 / W'"
sa=0 sb=0 sd=0
model=pfet_01v8
spiceprefix=X
}
C {madvlsi/gnd.sym} -1270 1240 0 0 {name=l5 lab=GND}
C {madvlsi/vdd.sym} -1270 1200 0 0 {name=l6 lab=VDD}
C {madvlsi/gnd.sym} -1270 420 0 0 {name=l7 lab=GND}
C {madvlsi/vdd.sym} -1270 380 0 0 {name=l8 lab=VDD}
C {devices/ipin.sym} -1380 750 0 0 {name=p4 lab=V1}
C {devices/ipin.sym} -1380 830 0 0 {name=p5 lab=V2}
C {devices/opin.sym} -1380 790 2 0 {name=p6 lab=VOUT}
C {madvlsi/nmos3.sym} -240 950 1 0 {name=MD1
L=.6
W=1.5
body=GND
nf=1
mult=1
ad="'int((nf+1)/2) * W/nf * 0.29'" 
pd="'2*int((nf+1)/2) * (W/nf + 0.29)'"
as="'int((nf+2)/2) * W/nf * 0.29'" 
ps="'2*int((nf+2)/2) * (W/nf + 0.29)'"
nrd="'0.29 / W'" nrs="'0.29 / W'"
sa=0 sb=0 sd=0
model=nfet_01v8
spiceprefix=X
}
C {madvlsi/nmos3.sym} -240 1050 1 0 {name=MD2
L=.6
W=1.5
body=GND
nf=1
mult=1
ad="'int((nf+1)/2) * W/nf * 0.29'" 
pd="'2*int((nf+1)/2) * (W/nf + 0.29)'"
as="'int((nf+2)/2) * W/nf * 0.29'" 
ps="'2*int((nf+2)/2) * (W/nf + 0.29)'"
nrd="'0.29 / W'" nrs="'0.29 / W'"
sa=0 sb=0 sd=0
model=nfet_01v8
spiceprefix=X
}
C {madvlsi/pmos3.sym} -240 570 3 0 {name=MD3
L=.6
W=1.5
body=VDD
nf=1
mult=1
ad="'int((nf+1)/2) * W/nf * 0.29'" 
pd="'2*int((nf+1)/2) * (W/nf + 0.29)'"
as="'int((nf+2)/2) * W/nf * 0.29'" 
ps="'2*int((nf+2)/2) * (W/nf + 0.29)'"
nrd="'0.29 / W'" nrs="'0.29 / W'"
sa=0 sb=0 sd=0
model=pfet_01v8
spiceprefix=X
}
C {madvlsi/pmos3.sym} -240 670 3 0 {name=MD4
L=.6
W=1.5
body=VDD
nf=1
mult=1
ad="'int((nf+1)/2) * W/nf * 0.29'" 
pd="'2*int((nf+1)/2) * (W/nf + 0.29)'"
as="'int((nf+2)/2) * W/nf * 0.29'" 
ps="'2*int((nf+2)/2) * (W/nf + 0.29)'"
nrd="'0.29 / W'" nrs="'0.29 / W'"
sa=0 sb=0 sd=0
model=pfet_01v8
spiceprefix=X
}
C {madvlsi/pmos3.sym} 1580 570 1 1 {name=M1
L=.6
W=1.5
body=VDD
nf=1
mult=1
ad="'int((nf+1)/2) * W/nf * 0.29'" 
pd="'2*int((nf+1)/2) * (W/nf + 0.29)'"
as="'int((nf+2)/2) * W/nf * 0.29'" 
ps="'2*int((nf+2)/2) * (W/nf + 0.29)'"
nrd="'0.29 / W'" nrs="'0.29 / W'"
sa=0 sb=0 sd=0
model=pfet_01v8
spiceprefix=X
}
C {madvlsi/pmos3.sym} 1460 570 1 1 {name=MD5
L=.6
W=1.5
body=VDD
nf=1
mult=1
ad="'int((nf+1)/2) * W/nf * 0.29'" 
pd="'2*int((nf+1)/2) * (W/nf + 0.29)'"
as="'int((nf+2)/2) * W/nf * 0.29'" 
ps="'2*int((nf+2)/2) * (W/nf + 0.29)'"
nrd="'0.29 / W'" nrs="'0.29 / W'"
sa=0 sb=0 sd=0
model=pfet_01v8
spiceprefix=X
}
C {madvlsi/pmos3.sym} 1580 670 1 1 {name=M6
L=.6
W=1.5
body=VDD
nf=1
mult=1
ad="'int((nf+1)/2) * W/nf * 0.29'" 
pd="'2*int((nf+1)/2) * (W/nf + 0.29)'"
as="'int((nf+2)/2) * W/nf * 0.29'" 
ps="'2*int((nf+2)/2) * (W/nf + 0.29)'"
nrd="'0.29 / W'" nrs="'0.29 / W'"
sa=0 sb=0 sd=0
model=pfet_01v8
spiceprefix=X
}
C {madvlsi/pmos3.sym} 1700 570 1 1 {name=M7
L=.6
W=1.5
body=VDD
nf=1
mult=1
ad="'int((nf+1)/2) * W/nf * 0.29'" 
pd="'2*int((nf+1)/2) * (W/nf + 0.29)'"
as="'int((nf+2)/2) * W/nf * 0.29'" 
ps="'2*int((nf+2)/2) * (W/nf + 0.29)'"
nrd="'0.29 / W'" nrs="'0.29 / W'"
sa=0 sb=0 sd=0
model=pfet_01v8
spiceprefix=X
}
C {madvlsi/pmos3.sym} 1700 670 1 1 {name=MD8
L=.6
W=1.5
body=VDD
nf=1
mult=1
ad="'int((nf+1)/2) * W/nf * 0.29'" 
pd="'2*int((nf+1)/2) * (W/nf + 0.29)'"
as="'int((nf+2)/2) * W/nf * 0.29'" 
ps="'2*int((nf+2)/2) * (W/nf + 0.29)'"
nrd="'0.29 / W'" nrs="'0.29 / W'"
sa=0 sb=0 sd=0
model=pfet_01v8
spiceprefix=X
}
C {madvlsi/pmos3.sym} 1460 670 1 1 {name=M9
L=.6
W=1.5
body=VDD
nf=1
mult=1
ad="'int((nf+1)/2) * W/nf * 0.29'" 
pd="'2*int((nf+1)/2) * (W/nf + 0.29)'"
as="'int((nf+2)/2) * W/nf * 0.29'" 
ps="'2*int((nf+2)/2) * (W/nf + 0.29)'"
nrd="'0.29 / W'" nrs="'0.29 / W'"
sa=0 sb=0 sd=0
model=pfet_01v8
spiceprefix=X
}
C {madvlsi/pmos3.sym} 1220 670 1 1 {name=M10
L=.6
W=1.5
body=VDD
nf=1
mult=1
ad="'int((nf+1)/2) * W/nf * 0.29'" 
pd="'2*int((nf+1)/2) * (W/nf + 0.29)'"
as="'int((nf+2)/2) * W/nf * 0.29'" 
ps="'2*int((nf+2)/2) * (W/nf + 0.29)'"
nrd="'0.29 / W'" nrs="'0.29 / W'"
sa=0 sb=0 sd=0
model=pfet_01v8
spiceprefix=X
}
C {madvlsi/pmos3.sym} 980 670 1 1 {name=MD11
L=.6
W=1.5
body=VDD
nf=1
mult=1
ad="'int((nf+1)/2) * W/nf * 0.29'" 
pd="'2*int((nf+1)/2) * (W/nf + 0.29)'"
as="'int((nf+2)/2) * W/nf * 0.29'" 
ps="'2*int((nf+2)/2) * (W/nf + 0.29)'"
nrd="'0.29 / W'" nrs="'0.29 / W'"
sa=0 sb=0 sd=0
model=pfet_01v8
spiceprefix=X
}
C {madvlsi/pmos3.sym} 1220 570 1 1 {name=M12
L=.6
W=1.5
body=VDD
nf=1
mult=1
ad="'int((nf+1)/2) * W/nf * 0.29'" 
pd="'2*int((nf+1)/2) * (W/nf + 0.29)'"
as="'int((nf+2)/2) * W/nf * 0.29'" 
ps="'2*int((nf+2)/2) * (W/nf + 0.29)'"
nrd="'0.29 / W'" nrs="'0.29 / W'"
sa=0 sb=0 sd=0
model=pfet_01v8
spiceprefix=X
}
C {madvlsi/pmos3.sym} 1340 670 1 1 {name=M13
L=.6
W=1.5
body=VDD
nf=1
mult=1
ad="'int((nf+1)/2) * W/nf * 0.29'" 
pd="'2*int((nf+1)/2) * (W/nf + 0.29)'"
as="'int((nf+2)/2) * W/nf * 0.29'" 
ps="'2*int((nf+2)/2) * (W/nf + 0.29)'"
nrd="'0.29 / W'" nrs="'0.29 / W'"
sa=0 sb=0 sd=0
model=pfet_01v8
spiceprefix=X
}
C {madvlsi/pmos3.sym} 1340 570 1 1 {name=MD14
L=.6
W=1.5
body=VDD
nf=1
mult=1
ad="'int((nf+1)/2) * W/nf * 0.29'" 
pd="'2*int((nf+1)/2) * (W/nf + 0.29)'"
as="'int((nf+2)/2) * W/nf * 0.29'" 
ps="'2*int((nf+2)/2) * (W/nf + 0.29)'"
nrd="'0.29 / W'" nrs="'0.29 / W'"
sa=0 sb=0 sd=0
model=pfet_01v8
spiceprefix=X
}
C {madvlsi/pmos3.sym} 980 570 1 1 {name=MD15
L=.6
W=1.5
body=VDD
nf=1
mult=1
ad="'int((nf+1)/2) * W/nf * 0.29'" 
pd="'2*int((nf+1)/2) * (W/nf + 0.29)'"
as="'int((nf+2)/2) * W/nf * 0.29'" 
ps="'2*int((nf+2)/2) * (W/nf + 0.29)'"
nrd="'0.29 / W'" nrs="'0.29 / W'"
sa=0 sb=0 sd=0
model=pfet_01v8
spiceprefix=X
}
C {madvlsi/pmos3.sym} 860 670 1 1 {name=M16
L=.6
W=1.5
body=VDD
nf=1
mult=1
ad="'int((nf+1)/2) * W/nf * 0.29'" 
pd="'2*int((nf+1)/2) * (W/nf + 0.29)'"
as="'int((nf+2)/2) * W/nf * 0.29'" 
ps="'2*int((nf+2)/2) * (W/nf + 0.29)'"
nrd="'0.29 / W'" nrs="'0.29 / W'"
sa=0 sb=0 sd=0
model=pfet_01v8
spiceprefix=X
}
C {madvlsi/pmos3.sym} 740 670 1 1 {name=M17
L=.6
W=1.5
body=VDD
nf=1
mult=1
ad="'int((nf+1)/2) * W/nf * 0.29'" 
pd="'2*int((nf+1)/2) * (W/nf + 0.29)'"
as="'int((nf+2)/2) * W/nf * 0.29'" 
ps="'2*int((nf+2)/2) * (W/nf + 0.29)'"
nrd="'0.29 / W'" nrs="'0.29 / W'"
sa=0 sb=0 sd=0
model=pfet_01v8
spiceprefix=X
}
C {madvlsi/pmos3.sym} 860 570 1 1 {name=M18
L=.6
W=1.5
body=VDD
nf=1
mult=1
ad="'int((nf+1)/2) * W/nf * 0.29'" 
pd="'2*int((nf+1)/2) * (W/nf + 0.29)'"
as="'int((nf+2)/2) * W/nf * 0.29'" 
ps="'2*int((nf+2)/2) * (W/nf + 0.29)'"
nrd="'0.29 / W'" nrs="'0.29 / W'"
sa=0 sb=0 sd=0
model=pfet_01v8
spiceprefix=X
}
C {madvlsi/pmos3.sym} 740 570 1 1 {name=M20
L=.6
W=1.5
body=VDD
nf=1
mult=1
ad="'int((nf+1)/2) * W/nf * 0.29'" 
pd="'2*int((nf+1)/2) * (W/nf + 0.29)'"
as="'int((nf+2)/2) * W/nf * 0.29'" 
ps="'2*int((nf+2)/2) * (W/nf + 0.29)'"
nrd="'0.29 / W'" nrs="'0.29 / W'"
sa=0 sb=0 sd=0
model=pfet_01v8
spiceprefix=X
}
C {madvlsi/pmos3.sym} 620 670 1 1 {name=M21
L=.6
W=1.5
body=VDD
nf=1
mult=1
ad="'int((nf+1)/2) * W/nf * 0.29'" 
pd="'2*int((nf+1)/2) * (W/nf + 0.29)'"
as="'int((nf+2)/2) * W/nf * 0.29'" 
ps="'2*int((nf+2)/2) * (W/nf + 0.29)'"
nrd="'0.29 / W'" nrs="'0.29 / W'"
sa=0 sb=0 sd=0
model=pfet_01v8
spiceprefix=X
}
C {madvlsi/pmos3.sym} 500 670 1 1 {name=M24
L=.6
W=1.5
body=VDD
nf=1
mult=1
ad="'int((nf+1)/2) * W/nf * 0.29'" 
pd="'2*int((nf+1)/2) * (W/nf + 0.29)'"
as="'int((nf+2)/2) * W/nf * 0.29'" 
ps="'2*int((nf+2)/2) * (W/nf + 0.29)'"
nrd="'0.29 / W'" nrs="'0.29 / W'"
sa=0 sb=0 sd=0
model=pfet_01v8
spiceprefix=X
}
C {madvlsi/pmos3.sym} 620 570 1 1 {name=M27
L=.6
W=1.5
body=VDD
nf=1
mult=1
ad="'int((nf+1)/2) * W/nf * 0.29'" 
pd="'2*int((nf+1)/2) * (W/nf + 0.29)'"
as="'int((nf+2)/2) * W/nf * 0.29'" 
ps="'2*int((nf+2)/2) * (W/nf + 0.29)'"
nrd="'0.29 / W'" nrs="'0.29 / W'"
sa=0 sb=0 sd=0
model=pfet_01v8
spiceprefix=X
}
C {madvlsi/pmos3.sym} 500 570 1 1 {name=M30
L=.6
W=1.5
body=VDD
nf=1
mult=1
ad="'int((nf+1)/2) * W/nf * 0.29'" 
pd="'2*int((nf+1)/2) * (W/nf + 0.29)'"
as="'int((nf+2)/2) * W/nf * 0.29'" 
ps="'2*int((nf+2)/2) * (W/nf + 0.29)'"
nrd="'0.29 / W'" nrs="'0.29 / W'"
sa=0 sb=0 sd=0
model=pfet_01v8
spiceprefix=X
}
C {madvlsi/nmos3.sym} 1580 1050 3 1 {name=M31
L=.6
W=1.5
body=GND
nf=1
mult=1
ad="'int((nf+1)/2) * W/nf * 0.29'" 
pd="'2*int((nf+1)/2) * (W/nf + 0.29)'"
as="'int((nf+2)/2) * W/nf * 0.29'" 
ps="'2*int((nf+2)/2) * (W/nf + 0.29)'"
nrd="'0.29 / W'" nrs="'0.29 / W'"
sa=0 sb=0 sd=0
model=nfet_01v8
spiceprefix=X
}
C {madvlsi/nmos3.sym} 1460 1050 3 1 {name=MD32
L=.6
W=1.5
body=GND
nf=1
mult=1
ad="'int((nf+1)/2) * W/nf * 0.29'" 
pd="'2*int((nf+1)/2) * (W/nf + 0.29)'"
as="'int((nf+2)/2) * W/nf * 0.29'" 
ps="'2*int((nf+2)/2) * (W/nf + 0.29)'"
nrd="'0.29 / W'" nrs="'0.29 / W'"
sa=0 sb=0 sd=0
model=nfet_01v8
spiceprefix=X
}
C {madvlsi/nmos3.sym} 1580 950 3 1 {name=M41
L=.6
W=1.5
body=GND
nf=1
mult=1
ad="'int((nf+1)/2) * W/nf * 0.29'" 
pd="'2*int((nf+1)/2) * (W/nf + 0.29)'"
as="'int((nf+2)/2) * W/nf * 0.29'" 
ps="'2*int((nf+2)/2) * (W/nf + 0.29)'"
nrd="'0.29 / W'" nrs="'0.29 / W'"
sa=0 sb=0 sd=0
model=nfet_01v8
spiceprefix=X
}
C {madvlsi/nmos3.sym} 1700 1050 3 1 {name=M44
L=.6
W=1.5
body=GND
nf=1
mult=1
ad="'int((nf+1)/2) * W/nf * 0.29'" 
pd="'2*int((nf+1)/2) * (W/nf + 0.29)'"
as="'int((nf+2)/2) * W/nf * 0.29'" 
ps="'2*int((nf+2)/2) * (W/nf + 0.29)'"
nrd="'0.29 / W'" nrs="'0.29 / W'"
sa=0 sb=0 sd=0
model=nfet_01v8
spiceprefix=X
}
C {madvlsi/nmos3.sym} 1700 950 3 1 {name=MD45
L=.6
W=1.5
body=GND
nf=1
mult=1
ad="'int((nf+1)/2) * W/nf * 0.29'" 
pd="'2*int((nf+1)/2) * (W/nf + 0.29)'"
as="'int((nf+2)/2) * W/nf * 0.29'" 
ps="'2*int((nf+2)/2) * (W/nf + 0.29)'"
nrd="'0.29 / W'" nrs="'0.29 / W'"
sa=0 sb=0 sd=0
model=nfet_01v8
spiceprefix=X
}
C {madvlsi/nmos3.sym} 1460 950 3 1 {name=M47
L=.6
W=1.5
body=GND
nf=1
mult=1
ad="'int((nf+1)/2) * W/nf * 0.29'" 
pd="'2*int((nf+1)/2) * (W/nf + 0.29)'"
as="'int((nf+2)/2) * W/nf * 0.29'" 
ps="'2*int((nf+2)/2) * (W/nf + 0.29)'"
nrd="'0.29 / W'" nrs="'0.29 / W'"
sa=0 sb=0 sd=0
model=nfet_01v8
spiceprefix=X
}
C {madvlsi/nmos3.sym} 1220 950 3 1 {name=M50
L=.6
W=1.5
body=GND
nf=1
mult=1
ad="'int((nf+1)/2) * W/nf * 0.29'" 
pd="'2*int((nf+1)/2) * (W/nf + 0.29)'"
as="'int((nf+2)/2) * W/nf * 0.29'" 
ps="'2*int((nf+2)/2) * (W/nf + 0.29)'"
nrd="'0.29 / W'" nrs="'0.29 / W'"
sa=0 sb=0 sd=0
model=nfet_01v8
spiceprefix=X
}
C {madvlsi/nmos3.sym} 980 950 3 1 {name=MD52
L=.6
W=1.5
body=GND
nf=1
mult=1
ad="'int((nf+1)/2) * W/nf * 0.29'" 
pd="'2*int((nf+1)/2) * (W/nf + 0.29)'"
as="'int((nf+2)/2) * W/nf * 0.29'" 
ps="'2*int((nf+2)/2) * (W/nf + 0.29)'"
nrd="'0.29 / W'" nrs="'0.29 / W'"
sa=0 sb=0 sd=0
model=nfet_01v8
spiceprefix=X
}
C {madvlsi/nmos3.sym} 1220 1050 3 1 {name=M53
L=.6
W=1.5
body=GND
nf=1
mult=1
ad="'int((nf+1)/2) * W/nf * 0.29'" 
pd="'2*int((nf+1)/2) * (W/nf + 0.29)'"
as="'int((nf+2)/2) * W/nf * 0.29'" 
ps="'2*int((nf+2)/2) * (W/nf + 0.29)'"
nrd="'0.29 / W'" nrs="'0.29 / W'"
sa=0 sb=0 sd=0
model=nfet_01v8
spiceprefix=X
}
C {madvlsi/nmos3.sym} 1340 950 3 1 {name=M57
L=.6
W=1.5
body=GND
nf=1
mult=1
ad="'int((nf+1)/2) * W/nf * 0.29'" 
pd="'2*int((nf+1)/2) * (W/nf + 0.29)'"
as="'int((nf+2)/2) * W/nf * 0.29'" 
ps="'2*int((nf+2)/2) * (W/nf + 0.29)'"
nrd="'0.29 / W'" nrs="'0.29 / W'"
sa=0 sb=0 sd=0
model=nfet_01v8
spiceprefix=X
}
C {madvlsi/nmos3.sym} 1340 1050 3 1 {name=MD58
L=.6
W=1.5
body=GND
nf=1
mult=1
ad="'int((nf+1)/2) * W/nf * 0.29'" 
pd="'2*int((nf+1)/2) * (W/nf + 0.29)'"
as="'int((nf+2)/2) * W/nf * 0.29'" 
ps="'2*int((nf+2)/2) * (W/nf + 0.29)'"
nrd="'0.29 / W'" nrs="'0.29 / W'"
sa=0 sb=0 sd=0
model=nfet_01v8
spiceprefix=X
}
C {madvlsi/nmos3.sym} 980 1050 3 1 {name=MD59
L=.6
W=1.5
body=GND
nf=1
mult=1
ad="'int((nf+1)/2) * W/nf * 0.29'" 
pd="'2*int((nf+1)/2) * (W/nf + 0.29)'"
as="'int((nf+2)/2) * W/nf * 0.29'" 
ps="'2*int((nf+2)/2) * (W/nf + 0.29)'"
nrd="'0.29 / W'" nrs="'0.29 / W'"
sa=0 sb=0 sd=0
model=nfet_01v8
spiceprefix=X
}
C {madvlsi/nmos3.sym} 740 950 3 1 {name=M64
L=.6
W=1.5
body=GND
nf=1
mult=1
ad="'int((nf+1)/2) * W/nf * 0.29'" 
pd="'2*int((nf+1)/2) * (W/nf + 0.29)'"
as="'int((nf+2)/2) * W/nf * 0.29'" 
ps="'2*int((nf+2)/2) * (W/nf + 0.29)'"
nrd="'0.29 / W'" nrs="'0.29 / W'"
sa=0 sb=0 sd=0
model=nfet_01v8
spiceprefix=X
}
C {madvlsi/nmos3.sym} 620 950 3 1 {name=MD68
L=.6
W=1.5
body=GND
nf=1
mult=1
ad="'int((nf+1)/2) * W/nf * 0.29'" 
pd="'2*int((nf+1)/2) * (W/nf + 0.29)'"
as="'int((nf+2)/2) * W/nf * 0.29'" 
ps="'2*int((nf+2)/2) * (W/nf + 0.29)'"
nrd="'0.29 / W'" nrs="'0.29 / W'"
sa=0 sb=0 sd=0
model=nfet_01v8
spiceprefix=X
}
C {madvlsi/nmos3.sym} 740 1050 3 1 {name=M69
L=.6
W=1.5
body=GND
nf=1
mult=1
ad="'int((nf+1)/2) * W/nf * 0.29'" 
pd="'2*int((nf+1)/2) * (W/nf + 0.29)'"
as="'int((nf+2)/2) * W/nf * 0.29'" 
ps="'2*int((nf+2)/2) * (W/nf + 0.29)'"
nrd="'0.29 / W'" nrs="'0.29 / W'"
sa=0 sb=0 sd=0
model=nfet_01v8
spiceprefix=X
}
C {madvlsi/nmos3.sym} 860 950 3 1 {name=M70
L=.6
W=1.5
body=GND
nf=1
mult=1
ad="'int((nf+1)/2) * W/nf * 0.29'" 
pd="'2*int((nf+1)/2) * (W/nf + 0.29)'"
as="'int((nf+2)/2) * W/nf * 0.29'" 
ps="'2*int((nf+2)/2) * (W/nf + 0.29)'"
nrd="'0.29 / W'" nrs="'0.29 / W'"
sa=0 sb=0 sd=0
model=nfet_01v8
spiceprefix=X
}
C {madvlsi/nmos3.sym} 860 1050 3 1 {name=M71
L=.6
W=1.5
body=GND
nf=1
mult=1
ad="'int((nf+1)/2) * W/nf * 0.29'" 
pd="'2*int((nf+1)/2) * (W/nf + 0.29)'"
as="'int((nf+2)/2) * W/nf * 0.29'" 
ps="'2*int((nf+2)/2) * (W/nf + 0.29)'"
nrd="'0.29 / W'" nrs="'0.29 / W'"
sa=0 sb=0 sd=0
model=nfet_01v8
spiceprefix=X
}
C {madvlsi/nmos3.sym} 620 1050 3 1 {name=MD72
L=.6
W=1.5
body=GND
nf=1
mult=1
ad="'int((nf+1)/2) * W/nf * 0.29'" 
pd="'2*int((nf+1)/2) * (W/nf + 0.29)'"
as="'int((nf+2)/2) * W/nf * 0.29'" 
ps="'2*int((nf+2)/2) * (W/nf + 0.29)'"
nrd="'0.29 / W'" nrs="'0.29 / W'"
sa=0 sb=0 sd=0
model=nfet_01v8
spiceprefix=X
}
C {madvlsi/nmos3.sym} 500 950 3 1 {name=M73
L=.6
W=1.5
body=GND
nf=1
mult=1
ad="'int((nf+1)/2) * W/nf * 0.29'" 
pd="'2*int((nf+1)/2) * (W/nf + 0.29)'"
as="'int((nf+2)/2) * W/nf * 0.29'" 
ps="'2*int((nf+2)/2) * (W/nf + 0.29)'"
nrd="'0.29 / W'" nrs="'0.29 / W'"
sa=0 sb=0 sd=0
model=nfet_01v8
spiceprefix=X
}
C {madvlsi/nmos3.sym} 500 1050 3 1 {name=M74
L=.6
W=1.5
body=GND
nf=1
mult=1
ad="'int((nf+1)/2) * W/nf * 0.29'" 
pd="'2*int((nf+1)/2) * (W/nf + 0.29)'"
as="'int((nf+2)/2) * W/nf * 0.29'" 
ps="'2*int((nf+2)/2) * (W/nf + 0.29)'"
nrd="'0.29 / W'" nrs="'0.29 / W'"
sa=0 sb=0 sd=0
model=nfet_01v8
spiceprefix=X
}
C {madvlsi/pmos3.sym} 1820 570 1 1 {name=M75
L=.6
W=1.5
body=VDD
nf=1
mult=1
ad="'int((nf+1)/2) * W/nf * 0.29'" 
pd="'2*int((nf+1)/2) * (W/nf + 0.29)'"
as="'int((nf+2)/2) * W/nf * 0.29'" 
ps="'2*int((nf+2)/2) * (W/nf + 0.29)'"
nrd="'0.29 / W'" nrs="'0.29 / W'"
sa=0 sb=0 sd=0
model=pfet_01v8
spiceprefix=X
}
C {madvlsi/pmos3.sym} 1820 670 1 1 {name=M76
L=.6
W=1.5
body=VDD
nf=1
mult=1
ad="'int((nf+1)/2) * W/nf * 0.29'" 
pd="'2*int((nf+1)/2) * (W/nf + 0.29)'"
as="'int((nf+2)/2) * W/nf * 0.29'" 
ps="'2*int((nf+2)/2) * (W/nf + 0.29)'"
nrd="'0.29 / W'" nrs="'0.29 / W'"
sa=0 sb=0 sd=0
model=pfet_01v8
spiceprefix=X
}
C {madvlsi/nmos3.sym} 1820 1050 3 1 {name=M77
L=.6
W=1.5
body=GND
nf=1
mult=1
ad="'int((nf+1)/2) * W/nf * 0.29'" 
pd="'2*int((nf+1)/2) * (W/nf + 0.29)'"
as="'int((nf+2)/2) * W/nf * 0.29'" 
ps="'2*int((nf+2)/2) * (W/nf + 0.29)'"
nrd="'0.29 / W'" nrs="'0.29 / W'"
sa=0 sb=0 sd=0
model=nfet_01v8
spiceprefix=X
}
C {madvlsi/nmos3.sym} 1820 950 3 1 {name=M78
L=.6
W=1.5
body=GND
nf=1
mult=1
ad="'int((nf+1)/2) * W/nf * 0.29'" 
pd="'2*int((nf+1)/2) * (W/nf + 0.29)'"
as="'int((nf+2)/2) * W/nf * 0.29'" 
ps="'2*int((nf+2)/2) * (W/nf + 0.29)'"
nrd="'0.29 / W'" nrs="'0.29 / W'"
sa=0 sb=0 sd=0
model=nfet_01v8
spiceprefix=X
}
C {madvlsi/nmos3.sym} 1920 1050 3 1 {name=MD79
L=.6
W=1.5
body=GND
nf=1
mult=1
ad="'int((nf+1)/2) * W/nf * 0.29'" 
pd="'2*int((nf+1)/2) * (W/nf + 0.29)'"
as="'int((nf+2)/2) * W/nf * 0.29'" 
ps="'2*int((nf+2)/2) * (W/nf + 0.29)'"
nrd="'0.29 / W'" nrs="'0.29 / W'"
sa=0 sb=0 sd=0
model=nfet_01v8
spiceprefix=X
}
C {madvlsi/nmos3.sym} 1920 950 3 1 {name=MD80
L=.6
W=1.5
body=GND
nf=1
mult=1
ad="'int((nf+1)/2) * W/nf * 0.29'" 
pd="'2*int((nf+1)/2) * (W/nf + 0.29)'"
as="'int((nf+2)/2) * W/nf * 0.29'" 
ps="'2*int((nf+2)/2) * (W/nf + 0.29)'"
nrd="'0.29 / W'" nrs="'0.29 / W'"
sa=0 sb=0 sd=0
model=nfet_01v8
spiceprefix=X
}
C {madvlsi/pmos3.sym} 1940 570 1 1 {name=MD81
L=.6
W=1.5
body=VDD
nf=1
mult=1
ad="'int((nf+1)/2) * W/nf * 0.29'" 
pd="'2*int((nf+1)/2) * (W/nf + 0.29)'"
as="'int((nf+2)/2) * W/nf * 0.29'" 
ps="'2*int((nf+2)/2) * (W/nf + 0.29)'"
nrd="'0.29 / W'" nrs="'0.29 / W'"
sa=0 sb=0 sd=0
model=pfet_01v8
spiceprefix=X
}
C {madvlsi/pmos3.sym} 1940 670 1 1 {name=MD82
L=.6
W=1.5
body=VDD
nf=1
mult=1
ad="'int((nf+1)/2) * W/nf * 0.29'" 
pd="'2*int((nf+1)/2) * (W/nf + 0.29)'"
as="'int((nf+2)/2) * W/nf * 0.29'" 
ps="'2*int((nf+2)/2) * (W/nf + 0.29)'"
nrd="'0.29 / W'" nrs="'0.29 / W'"
sa=0 sb=0 sd=0
model=pfet_01v8
spiceprefix=X
}
C {madvlsi/nmos3.sym} 1100 950 3 1 {name=MD83
L=.6
W=1.5
body=GND
nf=1
mult=1
ad="'int((nf+1)/2) * W/nf * 0.29'" 
pd="'2*int((nf+1)/2) * (W/nf + 0.29)'"
as="'int((nf+2)/2) * W/nf * 0.29'" 
ps="'2*int((nf+2)/2) * (W/nf + 0.29)'"
nrd="'0.29 / W'" nrs="'0.29 / W'"
sa=0 sb=0 sd=0
model=nfet_01v8
spiceprefix=X
}
C {madvlsi/nmos3.sym} 1100 1050 3 1 {name=MD84
L=.6
W=1.5
body=GND
nf=1
mult=1
ad="'int((nf+1)/2) * W/nf * 0.29'" 
pd="'2*int((nf+1)/2) * (W/nf + 0.29)'"
as="'int((nf+2)/2) * W/nf * 0.29'" 
ps="'2*int((nf+2)/2) * (W/nf + 0.29)'"
nrd="'0.29 / W'" nrs="'0.29 / W'"
sa=0 sb=0 sd=0
model=nfet_01v8
spiceprefix=X
}
C {madvlsi/pmos3.sym} 1100 570 1 1 {name=MD85
L=.6
W=1.5
body=VDD
nf=1
mult=1
ad="'int((nf+1)/2) * W/nf * 0.29'" 
pd="'2*int((nf+1)/2) * (W/nf + 0.29)'"
as="'int((nf+2)/2) * W/nf * 0.29'" 
ps="'2*int((nf+2)/2) * (W/nf + 0.29)'"
nrd="'0.29 / W'" nrs="'0.29 / W'"
sa=0 sb=0 sd=0
model=pfet_01v8
spiceprefix=X
}
C {madvlsi/pmos3.sym} 1100 670 1 1 {name=MD86
L=.6
W=1.5
body=VDD
nf=1
mult=1
ad="'int((nf+1)/2) * W/nf * 0.29'" 
pd="'2*int((nf+1)/2) * (W/nf + 0.29)'"
as="'int((nf+2)/2) * W/nf * 0.29'" 
ps="'2*int((nf+2)/2) * (W/nf + 0.29)'"
nrd="'0.29 / W'" nrs="'0.29 / W'"
sa=0 sb=0 sd=0
model=pfet_01v8
spiceprefix=X
}
C {sky130_fd_pr/cap_mim_m3_1.sym} -1320 790 0 0 {name=C1 model=cap_mim_m3_1 W=20 L=12 MF=1 spiceprefix=X}
